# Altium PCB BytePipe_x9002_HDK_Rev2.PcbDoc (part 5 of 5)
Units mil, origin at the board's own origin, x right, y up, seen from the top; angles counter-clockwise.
Board outline 4250 x 4250 mil, 8 copper layers (Top Layer, L2-GND, L3-SIG, L4-GND, L5-PWR, L6-SIG, L7-GND, Bottom Layer), stack 63 mil thick; 296 components, 250 nets, 1198 pads, 2326 vias.

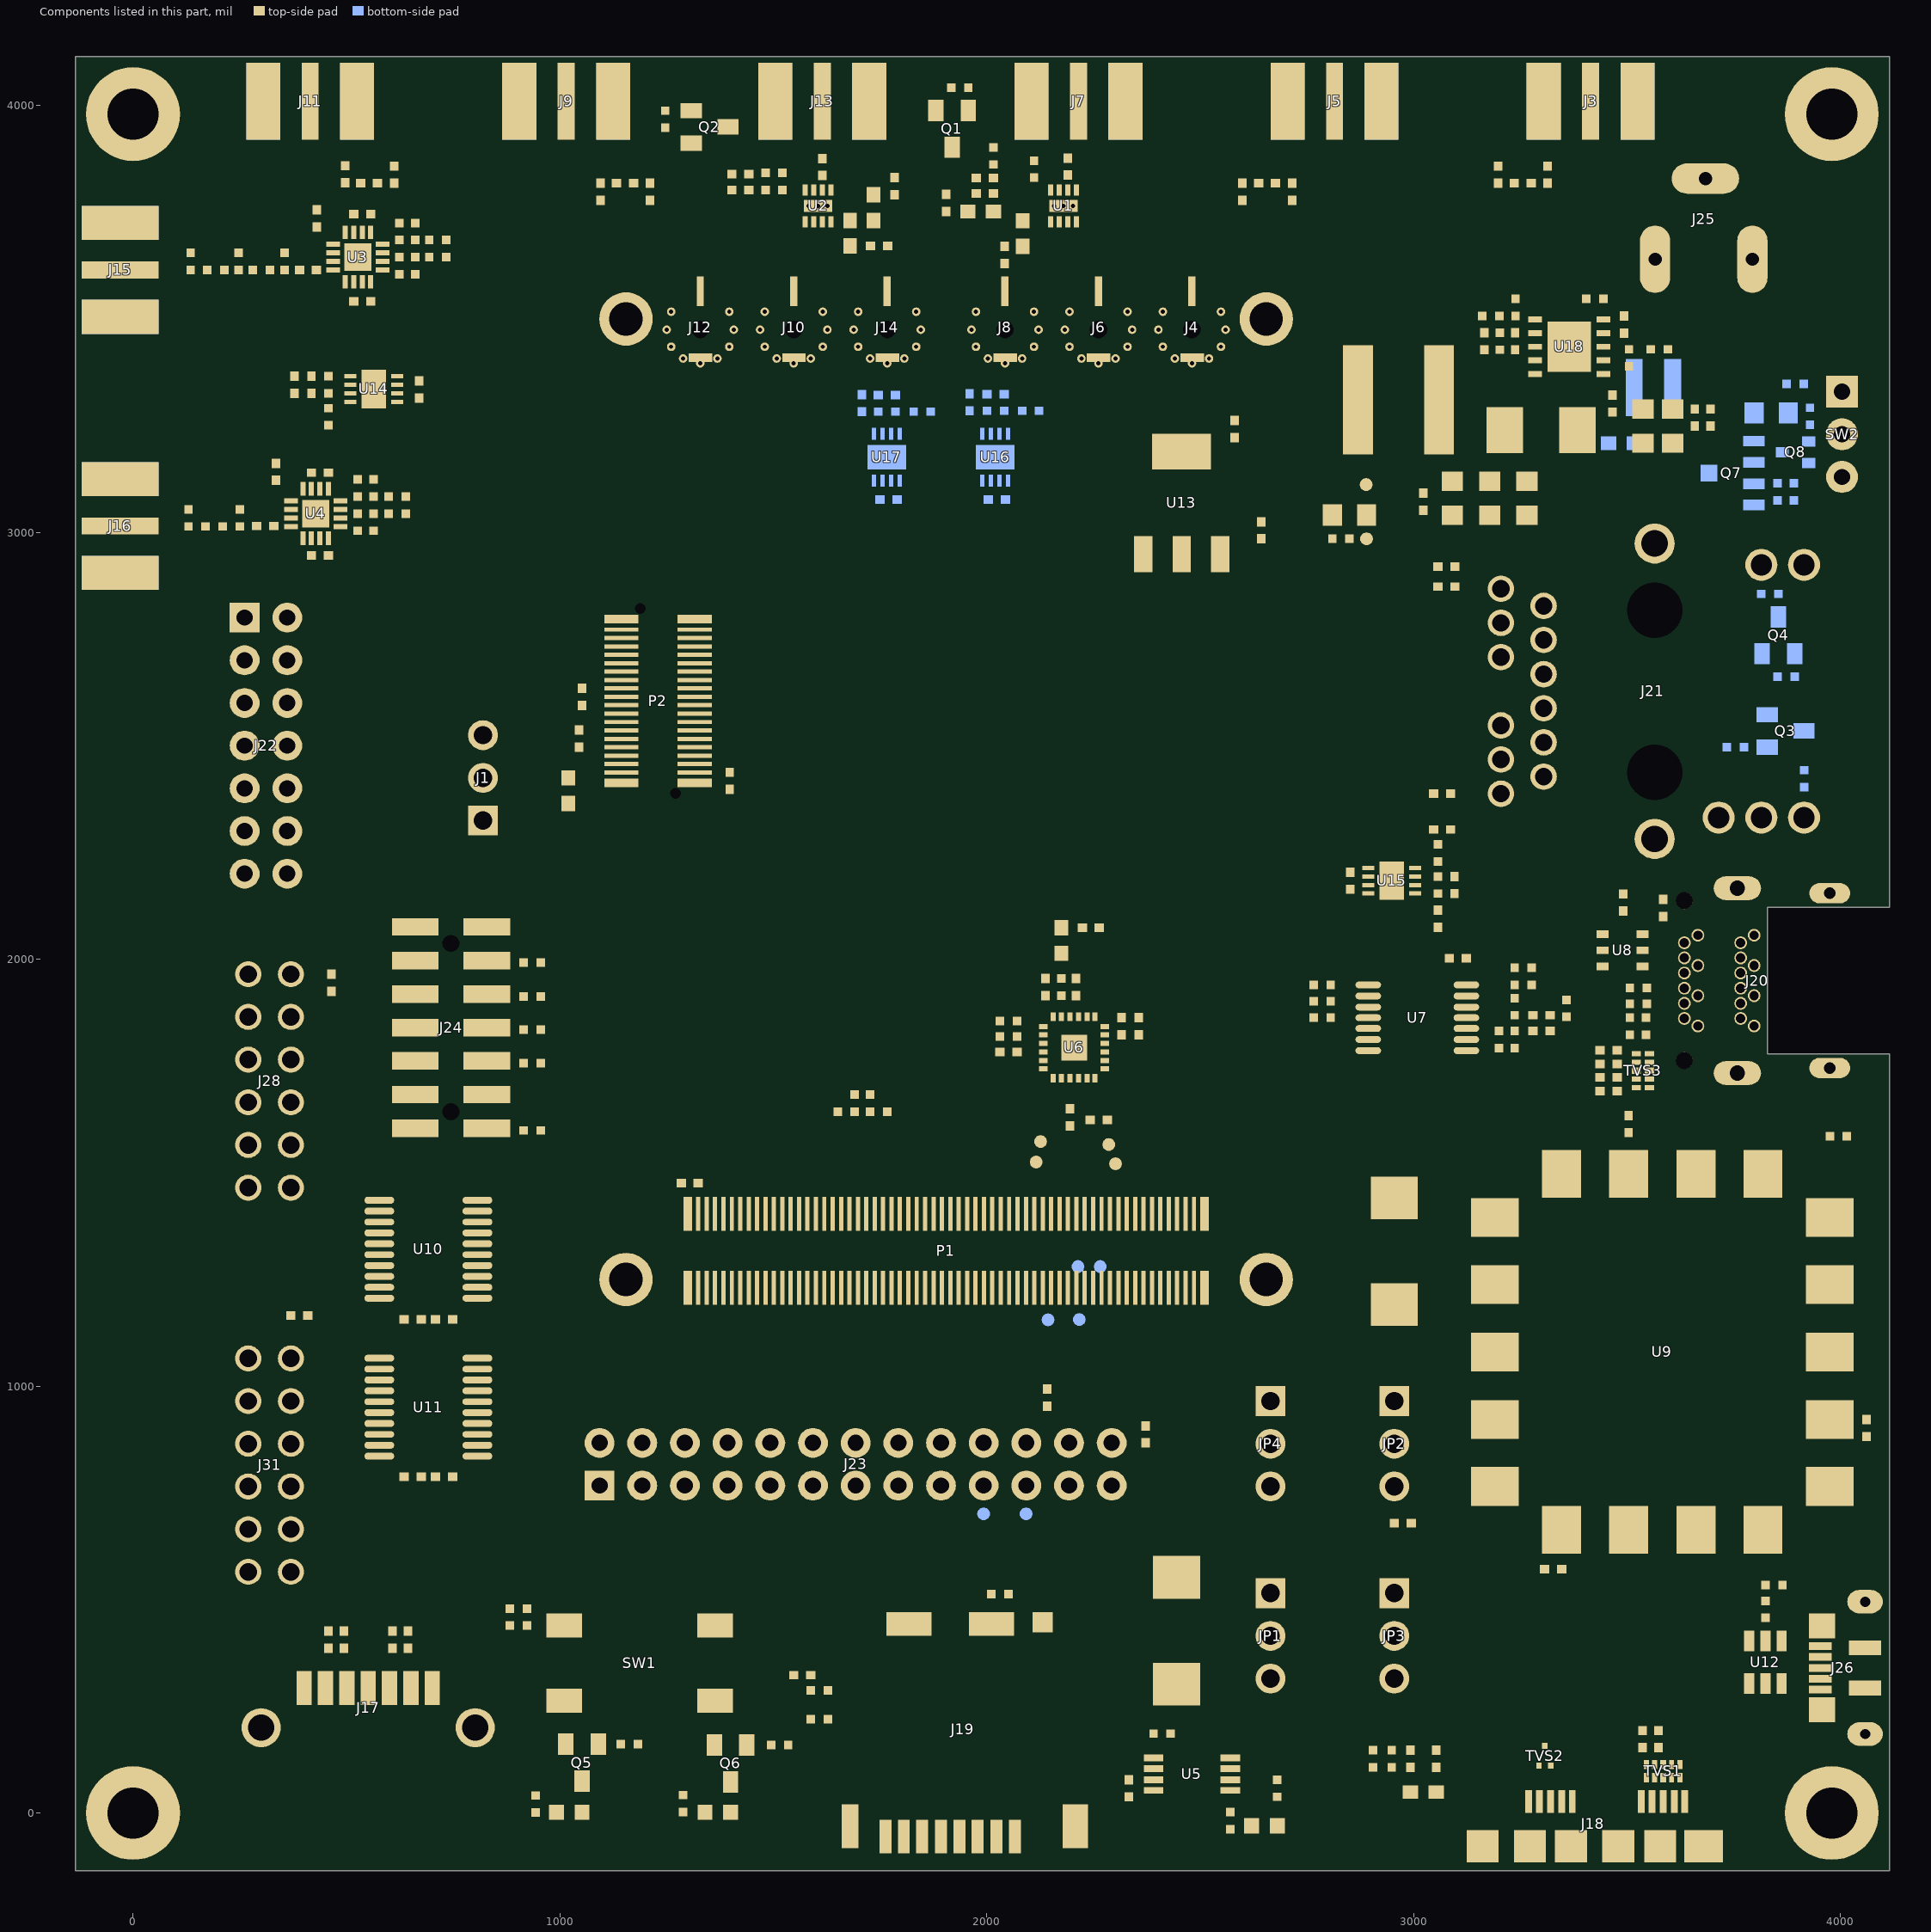
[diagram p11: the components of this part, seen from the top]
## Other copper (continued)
Bottom Layer:
  region net VCC5V0: 1761,3063.5 1761,3169 1731,3169 1731,3063.5
  region net VCC4V8_LNA1: 1757,3217 1757,3332 1735,3332 1735,3217
  region net VCC5V0: 2015,3069 2015,3169 1985,3169 1985,3069
  region net VCC4V8_LNA0: 2011,3217 2011,3334 1991,3334 1991,3217
  region net NetC73_2: 3607,3406 3711,3406 3711,3340 3643,3272 3607,3272
  text ".Layer_Name" at 2837.03,-398.88 h75

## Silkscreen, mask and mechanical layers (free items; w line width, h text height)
Top Overlay:
  drawing of 59 lines, arcs and shapes, not listed
  text "RX1B" at 3004,4048 h50
  text "RX2A" at 1248,4045 h50
  text "TX1" at 3604,4045 h50
  text "TX2" at 109,4040 h50
  text "RX1A" at 2408,4040 h50
  text "RX2B" at 658,4039 h50
  text "12V 2A" at 3659,3890 h40
  text "MCS" at -107,3803 h50
  text "ON" at 3771.5,3319.5 h40
  text "RF_CLK" at -117,3217 h50
  text "HDK_02" at 731.75,3188.74 h39.5 r270
  text "OFF" at 3770.5,3108.5 h40
  text "GND" at 83.5,2788.5 h30
  text "GND" at 438.5,2788.5 h30
  text "AUXADC_0" at -26.5,2689.5 h30
  text "AUXADC_1" at 436.5,2688.5 h30
  text "FAN" at 694.5,2600.5 h50
  text "GND" at 437.5,2586.5 h30
  text "GND" at 111.5,2584.5 h30
  text "RJ45 / ETHERNET" at 2853,2581 h35
  text "RFIC GPIO" at -94.5,2561 h50 r270
  text "AGPIO_2" at 432.5,2492.5 h30
  text "AGPIO_1" at 22.5,2484.5 h30
  text "AGPIO_4" at 433.5,2390.5 h30
  text "AGPIO_3" at 21.5,2385.5 h30
  text "AGPIO_6" at 432.5,2288.5 h30
  text "AGPIO_5" at 19.5,2285.5 h30
  text "DISPLAY" at 3832,2194 h50
  text "JTAG" at 657,2185 h50
  text "GND" at 433.5,2183.5 h30
  text "GND" at 112.5,2181.5 h30
  text "PMOD A" at -45.5,1309.5 h50
  text "UART1_RX" at 2005,935 h30 r90
  text "UART1_TX" at 1908,934 h30 r90
  text "GND" at 1107,932 h30 r90
  text "MIO43" at 1207.29,932 h30 r90
  text "MIO34" at 1307.57,932 h30 r90
  text "MIO42" at 1407.86,932 h30 r90
  text "MIO40" at 1508.14,932 h30 r90
  text "MIO44" at 1608.43,932 h30 r90
  text "MIO39" at 1708.71,932 h30 r90
  text "MIO41" at 1809,932 h30 r90
  text "GND" at 2208,932 h30 r90
  text "VCC3V3" at 2313,931 h30 r90
  text "VCC1V8" at 2107,930 h30 r90
  text "HOST" at 2882,923 h30 r90
  text "N/A" at 2585,922 h30 r90
  text "OTG" at 2587,747 h30 r90
  text "PWR SELECT" at 3089,707 h40 r90
  text "PS MIO" at 1023,704 h50 r90
  text "HRDW DETECT" at 2797,679 h40 r90
  text "OTG/ DEVICE" at 2881,639 h27 r90
  text "GND" at 2209,624 h30 r90
  text "MIO31" at 1307.5,597.78 h30 r90
  text "MIO36" at 1408,586.35 h30 r90
  text "MIO26" at 1609,586.35 h30 r90
  text "MIO32" at 1207,584.92 h30 r90
  text "MIO35" at 1508.5,584.92 h30 r90
  text "MIO33" at 1709.5,584.92 h30 r90
  text "MIO37" at 1810,584.92 h30 r90
  text "MIO38" at 1910.5,584.92 h30 r90
  text "GND" at 1107,577 h30 r90
  text "I2C_SCL" at 2105,563 h25 r90
  text "I2C_SDA" at 2006,561 h25 r90
  text "VCC3V3" at 2310,536 h30 r90
  text "SOM RESET" at 1066,505 h30
  text "OTG" at 2883,503 h30 r90
  text "SD CARD" at 2249,465 h50 r270
  text "JTAG Programmer" at 3246,423 h35
  text "OTG/ HOST" at 2592,419 h27 r90
  text "PMOD B" at -61.5,414.5 h50
  text "DEVICE" at 2591,241 h30 r90
  text "MODE SELECT" at 3091,223 h40 r90
  text "MODE SELECT" at 2798,220 h40 r90
  text "DEVICE/ HOST" at 2885,201 h27 r90
  text "SATA" at 154,117 h50 r90
  text "JTAG USB" at 3852,99 h50 r90
  text "PWR GOOD" at 1326,-103 h40
  text "PS DONE" at 956,-106 h40
  text "USB OVERCURRENT" at 2335,-110 h30
  text "USB  / 3.1-B" at 2916,-126 h45
  text ".Layer_Name" at 2837.03,-398.88 h75
Bottom Overlay:
  text ".Layer_Name" at 2837.03,-398.88 h75
Top Paste:
  text ".Layer_Name" at 2837.03,-398.88 h75
Bottom Paste:
  text ".Layer_Name" at 2837.03,-398.88 h75
Top Solder:
  text ".Layer_Name" at 2837.03,-398.88 h75
Bottom Solder:
  text ".Layer_Name" at 2837.03,-398.88 h75
Board Outline:
  the board outline again, w10
  text ".Layer_Name" at 2837.03,-398.88 h75
Assembly Top:
  the board outline again, w10
Assembly Bottom:
  the board outline again, w10
Sheet Graphics:
  drawing of 46 lines, arcs and shapes, not listed
  text "2" at 2433.03,6585.03 h180
  text "1" at 10933.03,6585.03 h180
  text "B" at -1624.97,4175.03 h280
  text "B" at 14755.03,4175.03 h280
  text "A" at 14726.03,-887.97 h280
  text "A" at -1624.97,-1324.97 h280
  text "NextGen RF Design, Inc." at 12660,-2125 h100
  text "2130 Howard Drive W" at 12652.03,-2309.15 h100
  text "North Mankato, MN 56003" at 12652.03,-2470.97 h100
  text "NEXTGEN RF DESIGN" at 11632.03,-2707.97 h100
  text "RF SOM" at 11626.03,-2849.97 h100
  text "Reference Designs ARE PROVIDED \"AS IS\" AND \"WITH ALL FAULTS. / NextGen DISCLAIMS ALL OTHER WARRANTIES, EXPRESS OR IMPLIED,  / NextGen may make changes to specifications and product descriptions at / any time, without notice. The Customer must not REGARDING PRODUCTS,  / INCLUDING BUT NOT LIMITED TO, ANY IMPLIED WARRANTIES OF / MERCHANTABILITY OR FITNESS FOR A PARTICULAR PURPOSE rely on / the absence or characteristics of any features or instructions marked / \"reserved\" or \"undefined.\"  NextGen reserves these for future definition and / shall have no responsibility whatsoever for conflicts or incompatibilities  / arising from future changes to them. The product information on the Web / Site or Materials is subject to change without notice. Do not finalize a / design with this information." at 8160,-2855 h40 r0.2
  text "ENGINEER" at 8343.03,-2954.97 h50
  text "ELLIOTT NELSON" at 9003.03,-2994.97 h50
  text "BYTEPIPE HARDWARE DEVELOPMENT KIT" at 11634.03,-2994.97 h100
  text "PCB DESIGNER" at 8343.03,-3154.97 h50
  text "SIZE" at 10443.03,-3154.97 h50
  text "CAGE NO." at 10763.03,-3154.97 h50
  text "CAD GENERATED:" at 11860.03,-3154.97 h50
  text "REV." at 14303.03,-3154.97 h50
  text "MIKE LARSEN" at 9003.03,-3194.97 h50
  text "\".pcb_File_Name_No_Path\"" at 11969.03,-3297.97 h125
  text "DATE" at 8343.03,-3334.97 h50
  text "B" at 10463.03,-3334.97 h100
  text "2" at 14303.03,-3334.97 h100
  text ".Print_Date" at 9003.03,-3374.97 h50
  text ".Print_Scale" at 10363.03,-3594.97 h50
  text "SHEET:" at 12863.03,-3594.97 h50
  text "1 OF 1" at 13593.03,-3594.97 h50
  text "2" at 2433.03,-3849.97 h180
  text "1" at 10933.03,-3849.97 h180
Gerber Title Block:
  drawing of 28 lines, arcs and shapes, not listed
  text "Project : BYTEPIPE Hardware Dev Kit" at -210,-385.01 h75
  text "Gerber Layer :" at 2050,-385.01 h75
  text "2130 Howard Drive W" at 360,-1220 h75
  text "North Mankato, MN 56003" at 360,-1360 h75
  text "Reference Designs ARE PROVIDED \"AS IS\" AND \"WITH ALL FAULTS. / NextGen DISCLAIMS ALL OTHER WARRANTIES, EXPRESS OR IMPLIED,  / NextGen may make changes to specifications and product descriptions at / any time, without notice. The Customer must not REGARDING PRODUCTS,  / INCLUDING BUT NOT LIMITED TO, ANY IMPLIED WARRANTIES OF / MERCHANTABILITY OR FITNESS FOR A PARTICULAR PURPOSE rely on / the absence or characteristics of any features or instructions marked / \"reserved\" or \"undefined.\"  NextGen reserves these for future definition and / shall have no responsibility whatsoever for conflicts or incompatibilities  / arising from future changes to them. The product information on the Web / Site or Materials is subject to change without notice. Do not finalize a / design with this information." at 2022.99,-1415.99 h40 r0.2
Drill Drawing:
  drawing of 663 lines, arcs and shapes, not listed
  text "DRILL TABLE" at 11220,4300 h100
  text "Symbol" at 9884.53,3967.73 h53.62
  text "Count" at 10217.47,3967.73 h53.62
  text "Hole Size" at 10622.11,3967.73 h53.62
  text "Plated" at 11359.9,3967.73 h53.62
  text "Hole Type" at 11647.66,3967.73 h53.62
  text "Drill Layer Pair" at 12078.64,3967.73 h53.62
  text "Via/Pad" at 12991.71,3967.73 h53.62
  text "307" at 10217.47,3856.02 h44.68
  text "8.00mil (0.203mm)" at 10622.11,3856.02 h44.68
  text "PTH" at 11359.9,3856.02 h44.68
  text "Round" at 11647.66,3856.02 h44.68
  text "Top Layer - Bottom Layer" at 12078.64,3856.02 h44.68
  text "Via" at 12991.71,3856.02 h44.68
  text "1980" at 10217.47,3744.31 h44.68
  text "8.00mil (0.203mm)" at 10622.11,3744.31 h44.68
  text "PTH" at 11359.9,3744.31 h44.68
  text "Round" at 11647.66,3744.31 h44.68
  text "Top Layer - Bottom Layer" at 12078.64,3744.31 h44.68
  text "Via" at 12991.71,3744.31 h44.68
  text "39" at 10217.47,3632.6 h44.68
  text "10.00mil (0.254mm)" at 10622.11,3632.6 h44.68
  text "PTH" at 11359.9,3632.6 h44.68
  text "Round" at 11647.66,3632.6 h44.68
  text "Top Layer - Bottom Layer" at 12078.64,3632.6 h44.68
  text "Via" at 12991.71,3632.6 h44.68
  text "H" at 9864.54,3627.61 h49.65
  text "60" at 10217.47,3520.89 h44.68
  text "10.00mil (0.254mm)" at 10622.11,3520.89 h44.68
  text "PTH" at 11359.9,3520.89 h44.68
  text "Round" at 11647.66,3520.89 h44.68
  text "Top Layer - Bottom Layer" at 12078.64,3520.89 h44.68
  text "Pad" at 12991.71,3520.89 h44.68
  text "20" at 10217.47,3409.18 h44.68
  text "22.00mil (0.559mm)" at 10622.11,3409.18 h44.68
  text "PTH" at 11359.9,3409.18 h44.68
  text "Round" at 11647.66,3409.18 h44.68
  text "Top Layer - Bottom Layer" at 12078.64,3409.18 h44.68
  text "Pad" at 12991.71,3409.18 h44.68
  text "C" at 9864.54,3404.19 h49.65
  text "2" at 10217.47,3297.47 h44.68
  text "24.00mil (0.610mm)" at 10622.11,3297.47 h44.68
  text "PTH" at 11359.9,3297.47 h44.68
  text "Slot" at 11647.66,3297.47 h44.68
  text "Top Layer - Bottom Layer" at 12078.64,3297.47 h44.68
  text "Pad" at 12991.71,3297.47 h44.68
  text "B" at 9864.54,3292.48 h49.65
  text "2" at 10217.47,3185.76 h44.68
  text "25.59mil (0.650mm)" at 10622.11,3185.76 h44.68
  text "NPTH" at 11359.9,3185.76 h44.68
  text "Round" at 11647.66,3185.76 h44.68
  text "Top Layer - Bottom Layer" at 12078.64,3185.76 h44.68
  text "Pad" at 12991.71,3185.76 h44.68
  text "2" at 10217.47,3074.05 h44.68
  text "27.56mil (0.700mm)" at 10622.11,3074.05 h44.68
  text "PTH" at 11359.9,3074.05 h44.68
  text "Slot" at 11647.66,3074.05 h44.68
  text "Top Layer - Bottom Layer" at 12078.64,3074.05 h44.68
  text "Pad" at 12991.71,3074.05 h44.68
  text "3" at 10217.47,2962.34 h44.68
  text "31.00mil (0.787mm)" at 10622.11,2962.34 h44.68
  text "PTH" at 11359.9,2962.34 h44.68
  text "Slot" at 11647.66,2962.34 h44.68
  text "Top Layer - Bottom Layer" at 12078.64,2962.34 h44.68
  text "Pad" at 12991.71,2962.34 h44.68
  text "2" at 10217.47,2850.63 h44.68
  text "35.43mil (0.900mm)" at 10622.11,2850.63 h44.68
  text "PTH" at 11359.9,2850.63 h44.68
  text "Slot" at 11647.66,2850.63 h44.68
  text "Top Layer - Bottom Layer" at 12078.64,2850.63 h44.68
  text "Pad" at 12991.71,2850.63 h44.68
  text "43" at 10217.47,2738.92 h44.68
  text "38.00mil (0.965mm)" at 10622.11,2738.92 h44.68
  text "PTH" at 11359.9,2738.92 h44.68
  text "Round" at 11647.66,2738.92 h44.68
  text "Top Layer - Bottom Layer" at 12078.64,2738.92 h44.68
  text "Pad" at 12991.71,2738.92 h44.68
  text "4" at 10217.47,2627.21 h44.68
  text "40.00mil (1.016mm)" at 10622.11,2627.21 h44.68
  text "NPTH" at 11359.9,2627.21 h44.68
  text "Round" at 11647.66,2627.21 h44.68
  text "Top Layer - Bottom Layer" at 12078.64,2627.21 h44.68
  text "Pad" at 12991.71,2627.21 h44.68
  text "A" at 9864.54,2622.22 h49.65
  text "24" at 10217.47,2515.5 h44.68
  text "40.95mil (1.040mm)" at 10622.11,2515.5 h44.68
  text "PTH" at 11359.9,2515.5 h44.68
  text "Round" at 11647.66,2515.5 h44.68
  text "Top Layer - Bottom Layer" at 12078.64,2515.5 h44.68
  text "Pad" at 12991.71,2515.5 h44.68
  text "6" at 10217.47,2403.79 h44.68
  text "41.00mil (1.041mm)" at 10622.11,2403.79 h44.68
  text "NPTH" at 11359.9,2403.79 h44.68
  text "Round" at 11647.66,2403.79 h44.68
  text "Top Layer - Bottom Layer" at 12078.64,2403.79 h44.68
  text "Pad" at 12991.71,2403.79 h44.68
  text "G" at 9864.54,2398.8 h49.65
  text "12" at 10217.47,2292.08 h44.68
  text "41.00mil (1.041mm)" at 10622.11,2292.08 h44.68
  text "PTH" at 11359.9,2292.08 h44.68
  text "Round" at 11647.66,2292.08 h44.68
  text "Top Layer - Bottom Layer" at 12078.64,2292.08 h44.68
  text "Pad" at 12991.71,2292.08 h44.68
  text "D" at 9864.54,2287.09 h49.65
  text "15" at 10217.47,2180.37 h44.68
  text "43.00mil (1.092mm)" at 10622.11,2180.37 h44.68
  text "PTH" at 11359.9,2180.37 h44.68
  text "Round" at 11647.66,2180.37 h44.68
  text "Top Layer - Bottom Layer" at 12078.64,2180.37 h44.68
  text "Pad" at 12991.71,2180.37 h44.68
  text "5" at 10217.47,2068.66 h44.68
  text "50.00mil (1.270mm)" at 10622.11,2068.66 h44.68
  text "PTH" at 11359.9,2068.66 h44.68
  text "Round" at 11647.66,2068.66 h44.68
  text "Top Layer - Bottom Layer" at 12078.64,2068.66 h44.68
  text "Pad" at 12991.71,2068.66 h44.68
  text "2" at 10217.47,1956.95 h44.68
  text "61.02mil (1.550mm)" at 10622.11,1956.95 h44.68
  text "PTH" at 11359.9,1956.95 h44.68
  text "Round" at 11647.66,1956.95 h44.68
  text "Top Layer - Bottom Layer" at 12078.64,1956.95 h44.68
  text "Pad" at 12991.71,1956.95 h44.68
  text "2" at 10217.47,1845.24 h44.68
  text "62.00mil (1.575mm)" at 10622.11,1845.24 h44.68
  text "PTH" at 11359.9,1845.24 h44.68
  text "Round" at 11647.66,1845.24 h44.68
  text "Top Layer - Bottom Layer" at 12078.64,1845.24 h44.68
  text "Pad" at 12991.71,1845.24 h44.68
  text "E" at 9864.54,1840.25 h49.65
  text "4" at 10217.47,1733.53 h44.68
  text "78.00mil (1.981mm)" at 10622.11,1733.53 h44.68
  text "PTH" at 11359.9,1733.53 h44.68
  text "Round" at 11647.66,1733.53 h44.68
  text "Top Layer - Bottom Layer" at 12078.64,1733.53 h44.68
  text "Pad" at 12991.71,1733.53 h44.68
  text "4" at 10217.47,1621.82 h44.68
  text "120.00mil (3.048mm)" at 10622.11,1621.82 h44.68
  text "PTH" at 11359.9,1621.82 h44.68
  text "Round" at 11647.66,1621.82 h44.68
  text "Top Layer - Bottom Layer" at 12078.64,1621.82 h44.68
  text "Pad" at 12991.71,1621.82 h44.68
  text "2" at 10217.47,1510.11 h44.68
  text "130.00mil (3.302mm)" at 10622.11,1510.11 h44.68
  text "NPTH" at 11359.9,1510.11 h44.68
  text "Round" at 11647.66,1510.11 h44.68
  text "Top Layer - Bottom Layer" at 12078.64,1510.11 h44.68
  text "Pad" at 12991.71,1510.11 h44.68
  text "F" at 9864.54,1505.12 h49.65
  text "2540 Total" at 10217.47,1398.4 h44.68
  text "Slot definitions :" at 9884.53,1295.32 h44.68
  text "Routed Path Length" at 10425.37,1295.32 h44.68
  text "= Calculated from tool start centre position to tool end centre position." at 11071.95,1295.32 h44.68
  text "Hole Length" at 10425.37,1225.76 h44.68
  text "= Routed Path Length + Tool Size = Slot length as defined in the PCB layout" at 10816.88,1225.76 h44.68
  text "LAYER STACK" at 11060,920 h100
  text "Layer" at 9433.3,603.01 h58.23
  text "Name" at 9831.72,603.01 h58.23
  text "Material" at 10734.66,603.01 h58.23
  text "Thickness" at 11569.67,603.01 h58.23
  text "Constant" at 12200.95,603.01 h58.23
  text "Board Layer Stack" at 12754.61,603.01 h58.23
  text "Top Overlay" at 9831.72,486.54 h58.23
  text "Top Solder" at 9831.72,370.08 h58.23
  text "Solder Resist" at 10734.66,370.08 h58.23
  text "0.40mil" at 11569.67,370.08 h58.23
  text "3.5" at 12200.95,370.08 h58.23
  text "1" at 9433.3,253.61 h58.23
  text "Top Layer" at 9831.72,253.61 h58.23
  text "CF-003" at 10734.66,253.61 h58.23
  text "1.40mil" at 11569.67,253.61 h58.23
  text "Dielectric 1" at 9831.72,137.15 h58.23
  text "370HR" at 10734.66,137.15 h58.23
  text "8.00mil" at 11569.67,137.15 h58.23
  text "4" at 12200.95,137.15 h58.23
  text "2" at 9433.3,20.69 h58.23
  text "L2-GND" at 9831.72,20.69 h58.23
  text "CF-004" at 10734.66,20.69 h58.23
  text "0.70mil" at 11569.67,20.69 h58.23
  text "Dielectric 2" at 9831.72,-95.78 h58.23
  text "370HR" at 10734.66,-95.78 h58.23
  text "8.00mil" at 11569.67,-95.78 h58.23
  text "4" at 12200.95,-95.78 h58.23
  text "3" at 9433.3,-212.24 h58.23
  text "L3-SIG" at 9831.72,-212.24 h58.23
  text "CF-004" at 10734.66,-212.24 h58.23
  text "0.70mil" at 11569.67,-212.24 h58.23
  text "Dielectric 3" at 9831.72,-328.7 h58.23
  text "370HR" at 10734.66,-328.7 h58.23
  text "8.00mil" at 11569.67,-328.7 h58.23
  text "4" at 12200.95,-328.7 h58.23
  text ".Layer_Name" at 2840,-400 h75
  text "FABRICATION NOTES: /  / 1. MATERIALS: /    ISOLA 370HR with 1/2 oz starting Copper and 1oz. copper plating. /        / 2. Board is 8 layers, finished board thickness = .062\" +/- 10%. /    Shall conform to IPC-2221, UL 94V-0 and European Directive 2011/65/EC (ROHS2). /     / 3. Finished board shall meet requirements of IPC-A-600. /    Finished trace width and outer diameter of plated holes shall be /    within .001\" or less of image on photo tool master. /    Annular rings to meet IPC-600J class 2. /     / 4. Holes to be plated through in accordance with IPC-600J. /     Dimensions shown are for finished plated through holes. /      / 5. All exposed copper to be finished with ENIG, as per IPC-4552.  /  / 6. Screen legend with white non-conductive ink, both sides.  / Contact areas of SMT components to be free of ink. /      / 7. SMOBC: BLACK LPI solder mask. Both sides. /     / 8. Board to be 100% bare board tested and report provided. /  / 9. Design rules used: 5mil trace, 5mil space. /  / 10. Plated holes have a +/- 0.003 inch tolerance. /     Non-plated +/- 0.0015 unless otherwise specified /  / 11. DO NOT adjust Stack-up or Trace widthes without contacting NEXTGEN RF." at 4460,-440 h80
  text "4" at 9433.3,-445.17 h58.23
  text "L4-GND" at 9831.72,-445.17 h58.23
  text "CF-004" at 10734.66,-445.17 h58.23
  text "0.70mil" at 11569.67,-445.17 h58.23
  text "Dielectric 4" at 9831.72,-561.63 h58.23
  text "370HR" at 10734.66,-561.63 h58.23
  text "8.00mil" at 11569.67,-561.63 h58.23
  text "4" at 12200.95,-561.63 h58.23
  text "5" at 9433.3,-678.09 h58.23
  text "L5-PWR" at 9831.72,-678.09 h58.23
  text "CF-004" at 10734.66,-678.09 h58.23
  text "0.70mil" at 11569.67,-678.09 h58.23
  text "Dielectric 5" at 9831.72,-794.56 h58.23
  text "370HR" at 10734.66,-794.56 h58.23
  text "8.00mil" at 11569.67,-794.56 h58.23
  text "4" at 12200.95,-794.56 h58.23
  text "6" at 9433.3,-911.02 h58.23
  text "L6-SIG" at 9831.72,-911.02 h58.23
  text "CF-004" at 10734.66,-911.02 h58.23
  text "0.70mil" at 11569.67,-911.02 h58.23
  text "Dielectric 6" at 9831.72,-1027.48 h58.23
  text "370HR" at 10734.66,-1027.48 h58.23
  text "8.00mil" at 11569.67,-1027.48 h58.23
  text "4" at 12200.95,-1027.48 h58.23
  text "7" at 9433.3,-1143.95 h58.23
  text "L7-GND" at 9831.72,-1143.95 h58.23
  text "CF-004" at 10734.66,-1143.95 h58.23
  text "0.70mil" at 11569.67,-1143.95 h58.23
  text "Dielectric 7" at 9831.72,-1260.41 h58.23
  text "370HR" at 10734.66,-1260.41 h58.23
  text "8.00mil" at 11569.67,-1260.41 h58.23
  text "4" at 12200.95,-1260.41 h58.23
  text "8" at 9433.3,-1376.88 h58.23
  text "Bottom Layer" at 9831.72,-1376.88 h58.23
  text "CF-003" at 10734.66,-1376.88 h58.23
  text "1.40mil" at 11569.67,-1376.88 h58.23
  text "Bottom Solder" at 9831.72,-1493.34 h58.23
  text "Solder Resist" at 10734.66,-1493.34 h58.23
  text "0.40mil" at 11569.67,-1493.34 h58.23
  text "3.5" at 12200.95,-1493.34 h58.23
  text "Bottom Overlay" at 9831.72,-1609.8 h58.23

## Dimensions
-135,4115 to -135,-135 on Fab/Dimensions
-135,4115 to 4115,4115 on Fab/Dimensions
